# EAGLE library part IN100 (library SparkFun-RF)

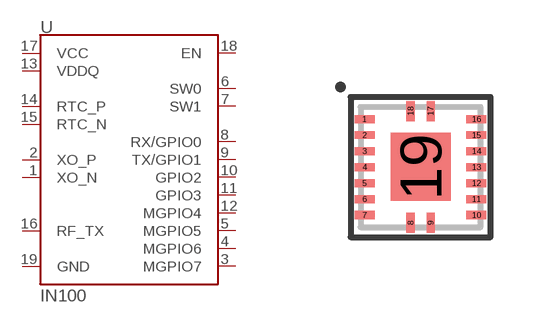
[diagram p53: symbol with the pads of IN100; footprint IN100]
Designator prefix U

## IN100 (PROD_ID: IC-17260)  [IN100]
1  XO_N
2  XO_P
3  MGPIO7
4  MGPIO6
5  MGPIO5
6  SW0  out
7  SW1  out
8  RX/GPIO0
9  TX/GPIO1
10  GPIO2
11  GPIO3
12  MGPIO4
13  VDDQ  pwr
14  RTC_P
15  RTC_N
16  RF_TX
17  VCC  pwr
18  EN  in
19  GND  pwr

## Footprint IN100 (pad centres in mm)
smd 0.5 x 0.2: 1 -1.4,1.2; 2 -1.4,0.8; 3 -1.4,0.4; 4 -1.4,0; 5 -1.4,-0.4; 6 -1.4,-0.8; 7 -1.4,-1.2; 10 1.4,-1.2; 11 1.4,-0.8; 12 1.4,-0.4; 13 1.4,0; 14 1.4,0.4; 15 1.4,0.8; 16 1.4,1.2
smd 0.2 x 0.5: 8 -0.25,-1.4; 9 0.25,-1.4; 17 0.25,1.4; 18 -0.25,1.4
smd 1.5 x 1.7: 19 0,0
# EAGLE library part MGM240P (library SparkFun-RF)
SiLabs MGM240P High performance wireless MCU Supports Zigbee, OpenThread, and BLE 26 GPIO pins Based on EFR32MG24 SoC 1.5MB Flash memory 256kB internal RAM

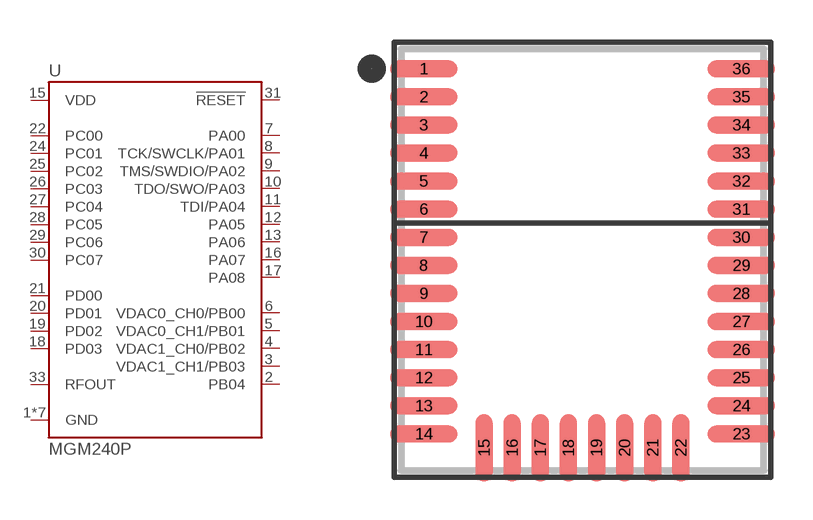
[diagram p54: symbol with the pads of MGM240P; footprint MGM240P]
Designator prefix U

## MGM240P (PROD_ID: IC-16860)  [MGM240P]
1  GND  pwr
2  PB04
3  VDAC1_CH1/PB03
4  VDAC1_CH0/PB02
5  VDAC0_CH1/PB01
6  VDAC0_CH0/PB00
7  PA00
8  TCK/SWCLK/PA01
9  TMS/SWDIO/PA02
10  TDO/SWO/PA03
11  TDI/PA04
12  PA05
13  PA06
14  GND  pwr
15  VDD  pwr
16  PA07
17  PA08
18  PD03
19  PD02
20  PD01
21  PD00
22  PC00
23  GND  pwr
24  PC01
25  PC02
26  PC03
27  PC04
28  PC05
29  PC06
30  PC07
31  !RESET!  in
32  GND  pwr
33  RFOUT  out
34  GND  pwr
35  GND  pwr
36  GND  pwr

## Footprint MGM240P (pad centres in mm)
MGM240P Specifications: Pin count: 36 Package size: 12.9mm x 15mm Pin pitch: 1mm
smd 2.4 x 0.6: 1 -5.65,6.8; 2 -5.65,5.8; 3 -5.65,4.8; 4 -5.65,3.8; 5 -5.65,2.8; 6 -5.65,1.8; 7 -5.65,0.8; 8 -5.65,-0.2; 9 -5.65,-1.2; 10 -5.65,-2.2; 11 -5.65,-3.2; 12 -5.65,-4.2; 13 -5.65,-5.2; 14 -5.65,-6.2; 23 5.65,-6.2; 24 5.65,-5.2; 25 5.65,-4.2; 26 5.65,-3.2; 27 5.65,-2.2; 28 5.65,-1.2; 29 5.65,-0.2; 30 5.65,0.8; 31 5.65,1.8; 32 5.65,2.8; 33 5.65,3.8; 34 5.65,4.8; 35 5.65,5.8; 36 5.65,6.8
smd 0.6 x 2.4: 15 -3.5,-6.7; 16 -2.5,-6.7; 17 -1.5,-6.7; 18 -0.5,-6.7; 19 0.5,-6.7; 20 1.5,-6.7; 21 2.5,-6.7; 22 3.5,-6.7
